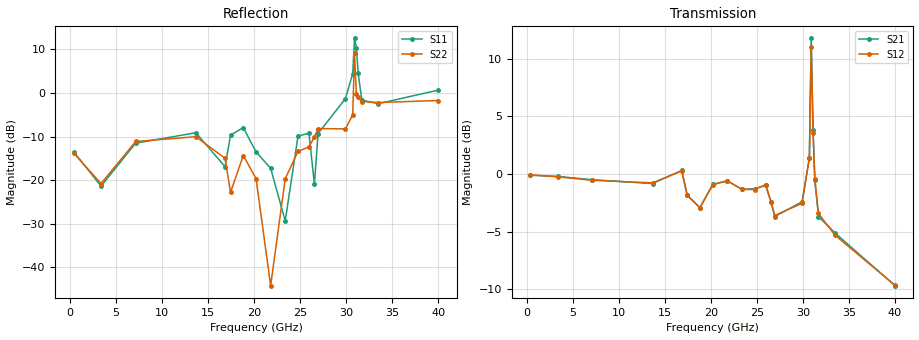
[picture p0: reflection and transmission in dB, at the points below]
! Network Analyzer HP8722ES.07.66: Jul 25, 2000 Serial No. US39175408
! 27 Oct 2004  08:15:48
! Frequency  S11  S21  S12  S22
# HZ  S  DB R  50
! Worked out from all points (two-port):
!   201 points, 400 MHz to 40 GHz, reference 50 ohm
!   highest |S21| = 11.79 dB at 30.89 GHz (marker M1); lowest = -9.7 dB at 40 GHz (marker M2)
!   |S21| within 3 dB of the highest: 30.83489 GHz to 30.96671 GHz (131.8 MHz wide, 0.427 % of centre)
!   lowest |S11| = -29.3 dB at 23.37 GHz (marker M3), VSWR 1.07, Z = 53.5 + j0.195 ohm
!   |S11| at or under -10 dB: start of sweep to 5.923 GHz; 6.061 GHz to 9.887 GHz (3.826 GHz wide, 48 % of centre); 19.42 GHz to 24.73 GHz (5.31 GHz wide, 24 % of centre) (the widest 3 of 5)
!   |S22| runs from -44.2 to 9.0 dB; largest |S21 - S12| = 1.7
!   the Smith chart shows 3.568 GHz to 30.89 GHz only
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4e8  -13.50 -84.0  -0.11 9.0  -0.06 10.3  -13.80 -78.6
3.37e9  -21.36 -94.8  -0.21 -11.6  -0.25 -11.9  -20.79 -98.4
7.132e9  -11.51 -104.8  -0.50 -17.5  -0.55 -18.0  -11.13 -110.2
1.3666e10  -9.13 -102.7  -0.83 -32.1  -0.77 -32.2  -10.03 -134.5
1.6834e10  -16.91 -74.7  0.31 -54.6  0.26 -54.6  -14.98 119.5
1.7428e10  -9.67 -54.6  -1.84 -56.1  -1.86 -56.7  -22.80 22.2
1.8814e10  -7.95 -77.9  -2.92 -41.0  -2.95 -40.8  -14.35 -79.0
2.02e10  -13.52 -85.5  -0.90 -43.8  -0.95 -43.8  -19.63 -131.8
2.1784e10  -17.27 -63.6  -0.60 -53.1  -0.58 -53.1  -44.20 115.3
2.3368e10  -29.35 3.1  -1.34 -63.6  -1.33 -63.1  -19.66 24.2
2.4754e10  -9.88 47.8  -1.29 -65.8  -1.36 -65.8  -13.42 36.7
2.5942e10  -9.22 4.8  -1.00 -75.2  -0.92 -75.8  -12.37 20.3
2.6536e10  -20.92 47.3  -2.45 -85.2  -2.40 -84.1  -10.10 29.9
2.6932e10  -9.32 80.0  -3.70 -77.0  -3.61 -77.9  -8.16 22.9
2.9902e10  -1.29 39.5  -2.41 -89.9  -2.55 -89.6  -8.25 -3.3
3.0694e10  4.43 26.1  1.39 -103.7  1.38 -103.1  -5.00 92.2
3.0892e10  12.52 97.7  11.79 56.8  11.05 31.3  9.05 -44.4
3.109e10  10.37 3.8  3.84 -21.9  3.57 -22.2  -0.29 -41.4
3.1288e10  4.52 -26.2  -0.55 -40.3  -0.45 -41.2  -1.02 -20.8
3.1684e10  -1.65 -25.9  -3.71 -71.9  -3.43 -71.7  -1.96 -13.6
3.3466e10  -2.46 -13.4  -5.12 -93.5  -5.31 -92.6  -2.19 -18.1
4e10  0.66 -29.2  -9.71 -126.8  -9.69 -126.6  -1.74 -49.8
